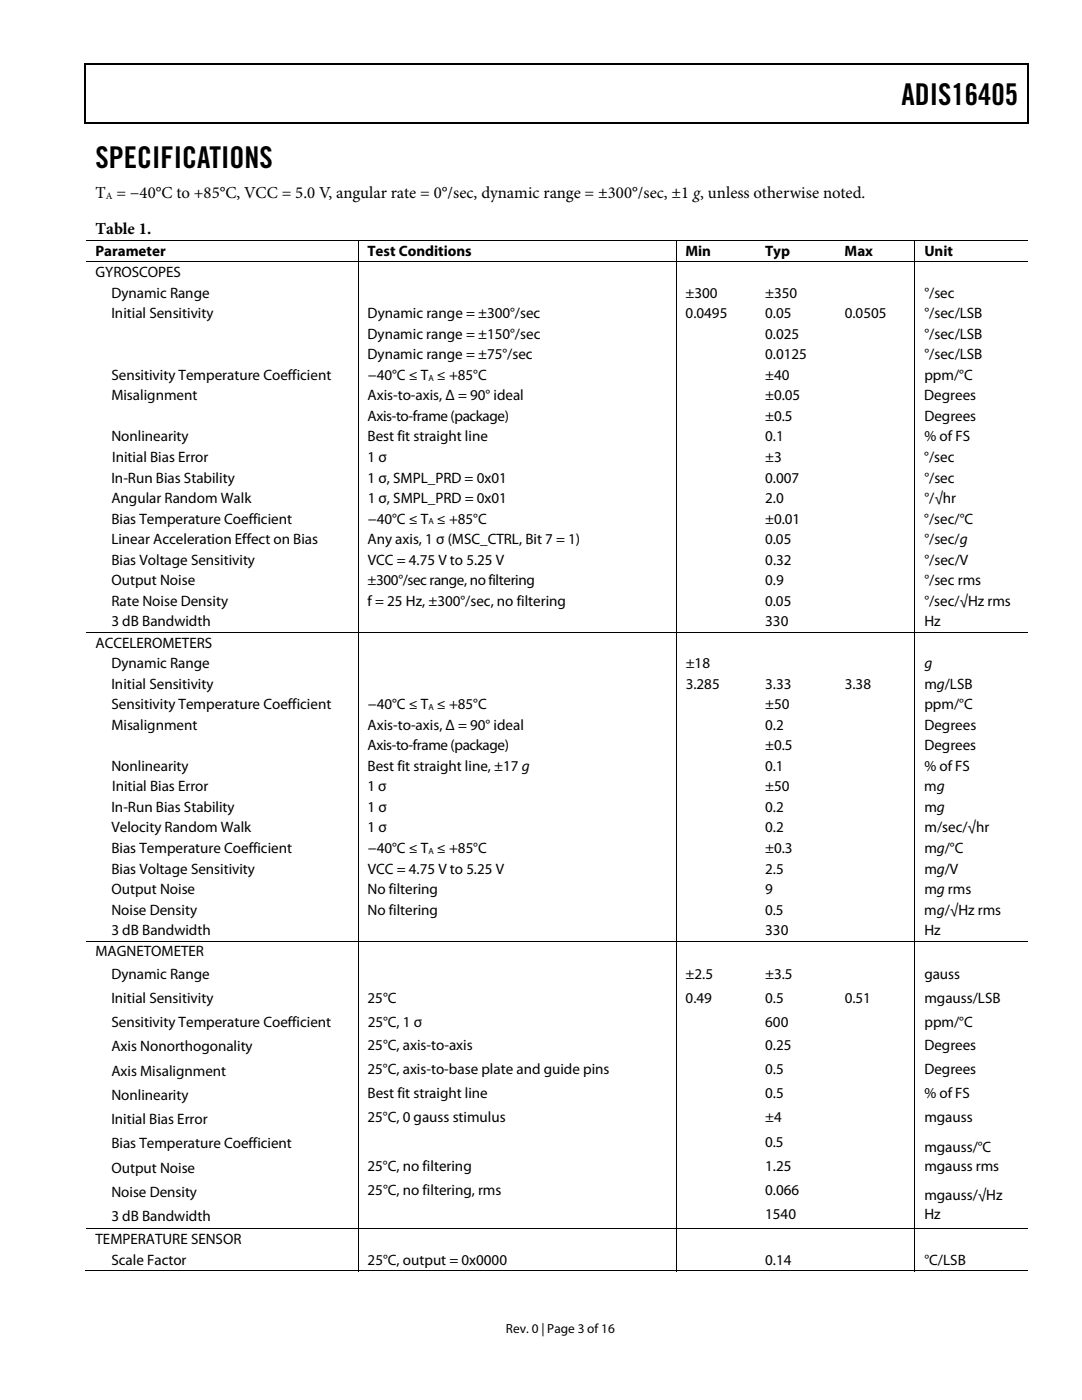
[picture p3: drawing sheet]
<svg xmlns="http://www.w3.org/2000/svg" width="216mm" height="279mm" viewBox="0 0 216 279" stroke-linecap="round" stroke-linejoin="round" font-family="sans-serif">
<defs><g id="words">
<g font-size="6">
<text x="179.9" y="21">ADIS16405</text>
<text x="19" y="33.6">SPECIFICATIONS</text>
</g>
<g font-size="3.3">
<text x="19" y="39.5">T = −40°C to +85°C, VCC = 5.0 V, angular rate = 0°/sec, dynamic range = ±300°/sec, ±1 g, unless otherwise noted.</text>
<text x="19" y="46.6">Table 1.</text>
</g>
<g font-size="3">
<text x="19" y="51.1">Parameter</text>
<text x="73.3" y="51.1">Test Conditions</text>
<text x="136.8" y="51.1">Min</text>
<text x="152.6" y="51.1">Typ</text>
<text x="168.5" y="51.1">Max</text>
<text x="184.4" y="51.1">Unit</text>
<text x="19" y="55.3">GYROSCOPES</text>
<text x="22.2" y="59.4">Dynamic Range</text>
<text x="136.8" y="59.4">±300</text>
<text x="152.7" y="59.4">±350</text>
<text x="184.5" y="59.4">°/sec</text>
<text x="22.2" y="63.5">Initial Sensitivity</text>
<text x="73.4" y="63.5">Dynamic range = ±300°/sec</text>
<text x="136.8" y="63.5">0.0495</text>
<text x="152.7" y="63.5">0.05</text>
<text x="168.6" y="63.5">0.0505</text>
<text x="184.5" y="63.5">°/sec/LSB</text>
<text x="73.3" y="67.6">Dynamic range = ±150°/sec</text>
<text x="73.3" y="71.7">Dynamic range = ±75°/sec</text>
<text x="152.7" y="67.6">0.025</text>
<text x="152.7" y="71.7">0.0125</text>
<text x="184.5" y="67.6">°/sec/LSB</text>
<text x="184.5" y="71.7">°/sec/LSB</text>
<text x="22.2" y="75.8">Sensitivity Temperature Coefficient</text>
<text x="73.4" y="75.8">−40°C ≤ T ≤ +85°C</text>
<text x="152.7" y="75.8">±40</text>
<text x="184.4" y="75.8">ppm/°C</text>
<text x="22.2" y="79.9">Misalignment</text>
<text x="73.3" y="79.9">Axis-to-axis, Δ = 90° ideal</text>
<text x="152.7" y="79.9">±0.05</text>
<text x="184.4" y="79.9">Degrees</text>
<text x="22.2" y="88.1">Nonlinearity</text>
<text x="73.3" y="84">Axis-to-frame (package)</text>
<text x="73.4" y="88.1">Best fit straight line</text>
<text x="152.7" y="84">±0.5</text>
<text x="152.7" y="88.1">0.1</text>
<text x="184.4" y="84">Degrees</text>
<text x="184.5" y="88.1">% of FS</text>
<text x="22.4" y="92.2">Initial Bias Error</text>
<text x="73.3" y="92.2">1 σ</text>
<text x="152.7" y="92.2">±3</text>
<text x="184.4" y="92.2">°/sec</text>
<text x="22.2" y="96.3">In-Run Bias Stability</text>
<text x="22.2" y="100.4">Angular Random Walk</text>
<text x="73.4" y="96.3">1 σ, SMPL_PRD = 0x01</text>
<text x="73.4" y="100.4">1 σ, SMPL_PRD = 0x01</text>
<text x="152.7" y="96.3">0.007</text>
<text x="152.7" y="100.4">2.0</text>
<text x="184.4" y="96.3">°/sec</text>
<text x="184.5" y="100.4">°/√hr</text>
<text x="22.2" y="104.5">Bias Temperature Coefficient</text>
<text x="73.4" y="104.5">−40°C ≤ T ≤ +85°C</text>
<text x="152.7" y="104.5">±0.01</text>
<text x="184.4" y="104.5">°/sec/°C</text>
<text x="22.2" y="108.6">Linear Acceleration Effect on Bias</text>
<text x="22.2" y="112.7">Bias Voltage Sensitivity</text>
<text x="73.3" y="108.6">Any axis, 1 σ (MSC_CTRL, Bit 7 = 1)</text>
<text x="73.4" y="112.7">VCC = 4.75 V to 5.25 V</text>
<text x="152.7" y="108.6">0.05</text>
<text x="152.7" y="112.7">0.32</text>
<text x="184.5" y="108.6">°/sec/g</text>
<text x="184.5" y="112.7">°/sec/V</text>
<text x="22.2" y="116.8">Output Noise</text>
<text x="73.3" y="116.8">±300°/sec range, no filtering</text>
<text x="152.7" y="116.8">0.9</text>
<text x="184.5" y="116.8">°/sec rms</text>
<text x="22.2" y="120.9">Rate Noise Density</text>
<text x="22.2" y="125">3 dB Bandwidth</text>
<text x="73.3" y="120.9">f = 25 Hz, ±300°/sec, no filtering</text>
<text x="152.7" y="120.9">0.05</text>
<text x="152.7" y="125">330</text>
<text x="184.4" y="120.9">°/sec/√Hz rms</text>
<text x="184.5" y="125">Hz</text>
<text x="19" y="129.2">ACCELEROMETERS</text>
<text x="22.2" y="133.3">Dynamic Range</text>
<text x="22.2" y="137.4">Initial Sensitivity</text>
<text x="136.8" y="133.3">±18</text>
<text x="136.8" y="137.4">3.285</text>
<text x="152.7" y="137.4">3.33</text>
<text x="168.6" y="137.4">3.38</text>
<text x="184.4" y="133.3">g</text>
<text x="184.5" y="137.4">mg/LSB</text>
<text x="22.2" y="141.5">Sensitivity Temperature Coefficient</text>
<text x="73.4" y="141.5">−40°C ≤ T ≤ +85°C</text>
<text x="152.7" y="141.5">±50</text>
<text x="184.4" y="141.5">ppm/°C</text>
<text x="22.2" y="145.6">Misalignment</text>
<text x="73.3" y="149.7">Axis-to-frame (package)</text>
<text x="73.4" y="145.6">Axis-to-axis, Δ = 90° ideal</text>
<text x="152.7" y="149.7">±0.5</text>
<text x="152.7" y="145.6">0.2</text>
<text x="184.4" y="149.7">Degrees</text>
<text x="184.5" y="145.6">Degrees</text>
<text x="22.2" y="153.8">Nonlinearity</text>
<text x="73.4" y="153.8">Best fit straight line, ±17 g</text>
<text x="152.7" y="153.8">0.1</text>
<text x="184.4" y="153.8">% of FS</text>
<text x="22.4" y="157.9">Initial Bias Error</text>
<text x="73.3" y="157.9">1 σ</text>
<text x="152.7" y="157.9">±50</text>
<text x="184.4" y="157.9">mg</text>
<text x="22.2" y="162">In-Run Bias Stability</text>
<text x="22.2" y="166.1">Velocity Random Walk</text>
<text x="73.4" y="162">1 σ</text>
<text x="73.4" y="166.1">1 σ</text>
<text x="152.7" y="162">0.2</text>
<text x="152.7" y="166.1">0.2</text>
<text x="184.5" y="162">mg</text>
<text x="184.5" y="166.1">m/sec/√hr</text>
<text x="22.2" y="170.2">Bias Temperature Coefficient</text>
<text x="73.4" y="170.2">−40°C ≤ T ≤ +85°C</text>
<text x="152.7" y="170.2">±0.3</text>
<text x="184.4" y="170.2">mg/°C</text>
<text x="22.2" y="174.3">Bias Voltage Sensitivity</text>
<text x="22.2" y="178.4">Output Noise</text>
<text x="73.3" y="178.4">No filtering</text>
<text x="73.4" y="174.3">VCC = 4.75 V to 5.25 V</text>
<text x="152.7" y="178.4">9</text>
<text x="152.7" y="174.3">2.5</text>
<text x="184.4" y="178.4">mg rms</text>
<text x="184.5" y="174.3">mg/V</text>
<text x="22.2" y="182.5">Noise Density</text>
<text x="73.3" y="182.5">No filtering</text>
<text x="152.7" y="182.5">0.5</text>
<text x="184.4" y="182.5">mg/√Hz rms</text>
<text x="19" y="190.9">MAGNETOMETER</text>
<text x="22.2" y="186.6">3 dB Bandwidth</text>
<text x="152.7" y="186.6">330</text>
<text x="184.5" y="186.6">Hz</text>
<text x="22.2" y="195.3">Dynamic Range</text>
<text x="136.8" y="195.3">±2.5</text>
<text x="152.7" y="195.3">±3.5</text>
<text x="184.4" y="195.3">gauss</text>
<text x="22.2" y="200.2">Initial Sensitivity</text>
<text x="73.4" y="200.2">25°C</text>
<text x="136.8" y="200.2">0.49</text>
<text x="152.7" y="200.2">0.5</text>
<text x="168.6" y="200.2">0.51</text>
<text x="184.4" y="200.2">mgauss/LSB</text>
<text x="22.2" y="205">Sensitivity Temperature Coefficient</text>
<text x="22.2" y="209.8">Axis Nonorthogonality</text>
<text x="73.3" y="209.5">25°C, axis-to-axis</text>
<text x="73.4" y="205">25°C, 1 σ</text>
<text x="152.7" y="209.5">0.25</text>
<text x="152.7" y="205">600</text>
<text x="184.4" y="209.5">Degrees</text>
<text x="184.5" y="205">ppm/°C</text>
<text x="22.2" y="214.7">Axis Misalignment</text>
<text x="73.3" y="214.3">25°C, axis-to-base plate and guide pins</text>
<text x="152.7" y="214.3">0.5</text>
<text x="184.4" y="214.3">Degrees</text>
<text x="22.2" y="219.5">Nonlinearity</text>
<text x="73.3" y="219.1">Best fit straight line</text>
<text x="152.7" y="219.1">0.5</text>
<text x="184.4" y="219.1">% of FS</text>
<text x="22.2" y="224.3">Initial Bias Error</text>
<text x="73.3" y="224">25°C, 0 gauss stimulus</text>
<text x="152.7" y="224">±4</text>
<text x="184.4" y="224">mgauss</text>
<text x="22.2" y="229.2">Bias Temperature Coefficient</text>
<text x="73.3" y="233.6">25°C, no filtering</text>
<text x="152.7" y="228.8">0.5</text>
<text x="152.7" y="233.6">1.25</text>
<text x="184.4" y="229.9">mgauss/°C</text>
<text x="184.4" y="233.6">mgauss rms</text>
<text x="22.2" y="234">Output Noise</text>
<text x="22.2" y="238.8">Noise Density</text>
<text x="73.3" y="238.5">25°C, no filtering, rms</text>
<text x="152.7" y="238.5">0.066</text>
<text x="184.4" y="239.5">mgauss/√Hz</text>
<text x="22.2" y="243.7">3 dB Bandwidth</text>
<text x="152.7" y="243.3">1540</text>
<text x="184.4" y="243.3">Hz</text>
<text x="19" y="248.3">TEMPERATURE SENSOR</text>
<text x="22.2" y="252.4">Scale Factor</text>
<text x="73.4" y="252.4">25°C, output = 0x0000</text>
<text x="152.7" y="252.4">0.14</text>
<text x="184.5" y="252.4">°C/LSB</text>
</g>
<text font-size="2.6" x="100.9" y="266">Rev. 0 | Page 3 of 16</text>
<text font-size="1.9" x="21.1" y="39.7">A</text>
<g font-size="1.8">
<text x="85.5" y="76">A</text>
<text x="85.5" y="104.7">A</text>
<text x="85.5" y="141.7">A</text>
<text x="85.5" y="170.4">A</text>
</g>
</g></defs>
<path d="M16.9 12.7h.2v1h-.2zM205.1 12.7h.2v1h-.2zM205.1 12.7h.2v.3h-.2zM82.3 24.4h.2v.3h-.2zM205.1 24.4h.2v.3h-.2z" fill="#000"/>
<path d="M16.9 12.8h188.2M17 13.7v11M205.2 13.7v11M205.1 24.5h-188.2" fill="none" stroke="#000" stroke-width=".25"/>
<g fill="none" stroke="#000" stroke-width=".2">
<path d="M17.1 47.9h188M17.1 52.3h188M71.4 48v4.2M71.4 52.3v73.8M134.9 48v4.2M134.9 52.3v73.8M182.5 48v4.2M182.5 52.3v73.8M17.1 126.2h188M71.4 126.3v61.4M134.9 126.3v61.4M182.5 126.3v61.4"/>
<path d="M17.1 187.8h188M71.4 187.9v57.3M134.9 187.9v57.3M182.5 187.9v57.3M16.9 253.6h54.5M17.1 245.2h188M71.4 245.3v8.4M71.5 253.6h63.3M134.9 245.3v8.4M135 253.6h47.5M182.5 245.3v8.4M182.6 253.6h22.5"/>
</g>
<use href="#words"/>
</svg>
